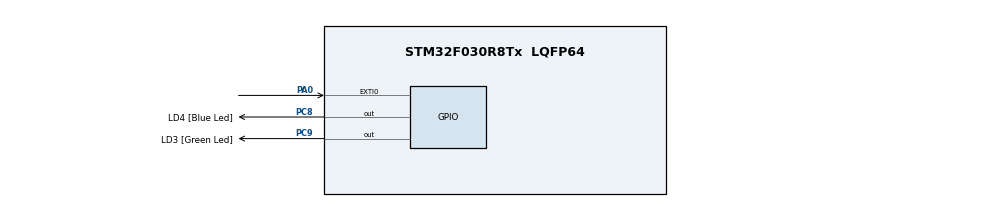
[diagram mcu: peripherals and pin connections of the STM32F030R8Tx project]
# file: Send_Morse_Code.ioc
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Mcu.Family=STM32F0
Mcu.Name=STM32F030R8Tx
Mcu.Package=LQFP64
NVIC.EXTI0_1_IRQn=true\:0\:0\:false\:false\:true\:true\:true
PA0.GPIO_ModeDefaultEXTI=GPIO_MODE_IT_FALLING
PA0.Signal=GPXTI0
PA13.GPIO_Label=SWDIO
PA13.Mode=Serial_Wire
PA13.Signal=SYS_SWDIO
PA14.GPIO_Label=SWCLK
PA14.Mode=Serial_Wire
PA14.Signal=SYS_SWCLK
PC8.GPIO_Label=LD4 [Blue Led]
PC8.Signal=GPIO_Output
PC9.GPIO_Label=LD3 [Green Led]
PC9.Signal=GPIO_Output
ProjectManager.HeapSize=0x200
ProjectManager.StackSize=0x400
ProjectManager.TargetToolchain=STM32CubeIDE
RCC.AHBCLKDivider=RCC_SYSCLK_DIV16
RCC.AHBFreq_Value=3000000
RCC.APB1Freq_Value=3000000
RCC.APB1TimFreq_Value=3000000
RCC.HCLKFreq_Value=3000000
RCC.PLLMUL=RCC_PLL_MUL12
RCC.SYSCLKFreq_VALUE=48000000
RCC.SYSCLKSource=RCC_SYSCLKSOURCE_PLLCLK
board=STM32F0308-DISCO

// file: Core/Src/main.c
/* USER CODE BEGIN Header */
/**
  ******************************************************************************
  * @file           : main.c
  * @brief          : Main program body
  ******************************************************************************
  * @attention
  *
  * <h2><center>&copy; Copyright (c) 2020 STMicroelectronics.
  * All rights reserved.</center></h2>
  *
  * This software component is licensed by ST under BSD 3-Clause license,
  * the "License"; You may not use this file except in compliance with the
  * License. You may obtain a copy of the License at:
  *                        opensource.org/licenses/BSD-3-Clause
  *
  ******************************************************************************
  */
/* USER CODE END Header */

#include "main.h"

/* USER CODE BEGIN Includes */
#include "stm32f0308_discovery.h"
/* USER CODE END Includes */

void SystemClock_Config(void);
static void MX_GPIO_Init(void);

int main(void)
{

  /* MCU Configuration--------------------------------------------------------*/

  /* Reset of all peripherals, Initializes the Flash interface and the Systick. */
  HAL_Init();

  /* Configure the system clock */
  SystemClock_Config();

  /* USER CODE BEGIN SysInit */
  SysTick_Config((SystemCoreClock/1000));
  /* USER CODE END SysInit */

  /* Initialize all configured peripherals */
  MX_GPIO_Init();
  /* USER CODE BEGIN 2 */
  BSP_LED_Init(LED_GREEN);
  /* USER CODE END 2 */

  /* Infinite loop */
  while (1)
  {

  }
}

void SystemClock_Config(void)
{
  RCC_OscInitTypeDef RCC_OscInitStruct = {0};
  RCC_ClkInitTypeDef RCC_ClkInitStruct = {0};

  /** Initializes the CPU, AHB and APB busses clocks
  */
  RCC_OscInitStruct.OscillatorType = RCC_OSCILLATORTYPE_HSI;
  RCC_OscInitStruct.HSIState = RCC_HSI_ON;
  RCC_OscInitStruct.HSICalibrationValue = RCC_HSICALIBRATION_DEFAULT;
  RCC_OscInitStruct.PLL.PLLState = RCC_PLL_ON;
  RCC_OscInitStruct.PLL.PLLSource = RCC_PLLSOURCE_HSI;
  RCC_OscInitStruct.PLL.PLLMUL = RCC_PLL_MUL12;
  RCC_OscInitStruct.PLL.PREDIV = RCC_PREDIV_DIV1;
  if (HAL_RCC_OscConfig(&RCC_OscInitStruct) != HAL_OK)
  {
    Error_Handler();
  }
  /** Initializes the CPU, AHB and APB busses clocks
  */
  RCC_ClkInitStruct.ClockType = RCC_CLOCKTYPE_HCLK|RCC_CLOCKTYPE_SYSCLK
                              |RCC_CLOCKTYPE_PCLK1;
  RCC_ClkInitStruct.SYSCLKSource = RCC_SYSCLKSOURCE_PLLCLK;
  RCC_ClkInitStruct.AHBCLKDivider = RCC_SYSCLK_DIV1;
  RCC_ClkInitStruct.APB1CLKDivider = RCC_HCLK_DIV1;

  if (HAL_RCC_ClockConfig(&RCC_ClkInitStruct, FLASH_LATENCY_1) != HAL_OK)
  {
    Error_Handler();
  }
}

static void MX_GPIO_Init(void)
{
  GPIO_InitTypeDef GPIO_InitStruct = {0};

  /* GPIO Ports Clock Enable */
  __HAL_RCC_GPIOA_CLK_ENABLE();
  __HAL_RCC_GPIOC_CLK_ENABLE();

  /*Configure GPIO pin Output Level */
  HAL_GPIO_WritePin(GPIOC, LD4_Pin|LD3_Pin, GPIO_PIN_RESET);

  /*Configure GPIO pin : PA0 */
  GPIO_InitStruct.Pin = GPIO_PIN_0;
  GPIO_InitStruct.Mode = GPIO_MODE_IT_FALLING;
  GPIO_InitStruct.Pull = GPIO_NOPULL;
  HAL_GPIO_Init(GPIOA, &GPIO_InitStruct);

  /*Configure GPIO pins : LD4_Pin LD3_Pin */
  GPIO_InitStruct.Pin = LD4_Pin|LD3_Pin;
  GPIO_InitStruct.Mode = GPIO_MODE_OUTPUT_PP;
  GPIO_InitStruct.Pull = GPIO_NOPULL;
  GPIO_InitStruct.Speed = GPIO_SPEED_FREQ_LOW;
  HAL_GPIO_Init(GPIOC, &GPIO_InitStruct);

  /* EXTI interrupt init*/
  HAL_NVIC_SetPriority(EXTI0_1_IRQn, 0, 0);
  HAL_NVIC_EnableIRQ(EXTI0_1_IRQn);

}

void Error_Handler(void)
{
}

/************************ (C) COPYRIGHT STMicroelectronics *****END OF FILE****/
